VERSION 5.8 ;
BUSBITCHARS "[]" ;
DIVIDERCHAR "/" ;
UNITS
    DATABASE MICRONS 2000 ;
END UNITS

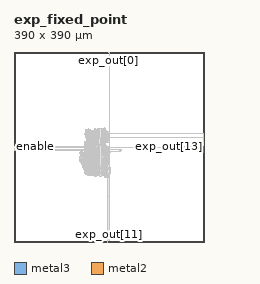
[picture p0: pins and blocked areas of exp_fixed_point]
MACRO exp_fixed_point
  FOREIGN exp_fixed_point 0 0 ;
  CLASS BLOCK ;
  SIZE 390 BY 390 ;
  PIN clk
    DIRECTION INPUT ;
    USE SIGNAL ;
    PORT
      LAYER metal3 ;
        RECT  0 194.915 0.07 194.985 ;
    END
  END clk
  PIN enable
    DIRECTION INPUT ;
    USE SIGNAL ;
    PORT
      LAYER metal3 ;
        RECT  0 195.755 0.07 195.825 ;
    END
  END enable
  PIN exp_out[0]
    DIRECTION OUTPUT ;
    USE SIGNAL ;
    PORT
      LAYER metal2 ;
        RECT  194.24 389.93 194.31 390 ;
    END
  END exp_out[0]
  PIN exp_out[10]
    DIRECTION OUTPUT ;
    USE SIGNAL ;
    PORT
      LAYER metal3 ;
        RECT  0 196.035 0.07 196.105 ;
    END
  END exp_out[10]
  PIN exp_out[11]
    DIRECTION OUTPUT ;
    USE SIGNAL ;
    PORT
      LAYER metal2 ;
        RECT  194.62 0 194.69 0.07 ;
    END
  END exp_out[11]
  PIN exp_out[12]
    DIRECTION OUTPUT ;
    USE SIGNAL ;
    PORT
      LAYER metal2 ;
        RECT  195 0 195.07 0.07 ;
    END
  END exp_out[12]
  PIN exp_out[13]
    DIRECTION OUTPUT ;
    USE SIGNAL ;
    PORT
      LAYER metal3 ;
        RECT  389.93 196.035 390 196.105 ;
    END
  END exp_out[13]
  PIN exp_out[14]
    DIRECTION OUTPUT ;
    USE SIGNAL ;
    PORT
      LAYER metal2 ;
        RECT  196.14 389.93 196.21 390 ;
    END
  END exp_out[14]
  PIN exp_out[15]
    DIRECTION OUTPUT ;
    USE SIGNAL ;
    PORT
      LAYER metal3 ;
        RECT  389.93 195.755 390 195.825 ;
    END
  END exp_out[15]
  PIN exp_out[1]
    DIRECTION OUTPUT ;
    USE SIGNAL ;
    PORT
      LAYER metal2 ;
        RECT  194.24 0 194.31 0.07 ;
    END
  END exp_out[1]
  PIN exp_out[2]
    DIRECTION OUTPUT ;
    USE SIGNAL ;
    PORT
      LAYER metal2 ;
        RECT  196.14 0 196.21 0.07 ;
    END
  END exp_out[2]
  PIN exp_out[3]
    DIRECTION OUTPUT ;
    USE SIGNAL ;
    PORT
      LAYER metal2 ;
        RECT  195.76 389.93 195.83 390 ;
    END
  END exp_out[3]
  PIN exp_out[4]
    DIRECTION OUTPUT ;
    USE SIGNAL ;
    PORT
      LAYER metal3 ;
        RECT  389.93 195.195 390 195.265 ;
    END
  END exp_out[4]
  PIN exp_out[5]
    DIRECTION OUTPUT ;
    USE SIGNAL ;
    PORT
      LAYER metal2 ;
        RECT  195.38 0 195.45 0.07 ;
    END
  END exp_out[5]
  PIN exp_out[6]
    DIRECTION OUTPUT ;
    USE SIGNAL ;
    PORT
      LAYER metal2 ;
        RECT  193.86 0 193.93 0.07 ;
    END
  END exp_out[6]
  PIN exp_out[7]
    DIRECTION OUTPUT ;
    USE SIGNAL ;
    PORT
      LAYER metal3 ;
        RECT  0 195.195 0.07 195.265 ;
    END
  END exp_out[7]
  PIN exp_out[8]
    DIRECTION OUTPUT ;
    USE SIGNAL ;
    PORT
      LAYER metal2 ;
        RECT  193.48 0 193.55 0.07 ;
    END
  END exp_out[8]
  PIN exp_out[9]
    DIRECTION OUTPUT ;
    USE SIGNAL ;
    PORT
      LAYER metal3 ;
        RECT  389.93 194.075 390 194.145 ;
    END
  END exp_out[9]
  PIN rst
    DIRECTION INPUT ;
    USE SIGNAL ;
    PORT
      LAYER metal3 ;
        RECT  0 194.355 0.07 194.425 ;
    END
  END rst
  PIN x_in[0]
    DIRECTION INPUT ;
    USE SIGNAL ;
    PORT
      LAYER metal3 ;
        RECT  389.93 195.475 390 195.545 ;
    END
  END x_in[0]
  PIN x_in[1]
    DIRECTION INPUT ;
    USE SIGNAL ;
    PORT
      LAYER metal2 ;
        RECT  195.76 0 195.83 0.07 ;
    END
  END x_in[1]
  PIN x_in[2]
    DIRECTION INPUT ;
    USE SIGNAL ;
    PORT
      LAYER metal3 ;
        RECT  0 195.475 0.07 195.545 ;
    END
  END x_in[2]
  PIN x_in[3]
    DIRECTION INPUT ;
    USE SIGNAL ;
    PORT
      LAYER metal3 ;
        RECT  0 194.635 0.07 194.705 ;
    END
  END x_in[3]
  PIN x_in[4]
    DIRECTION INPUT ;
    USE SIGNAL ;
    PORT
      LAYER metal2 ;
        RECT  195.38 389.93 195.45 390 ;
    END
  END x_in[4]
  PIN x_in[5]
    DIRECTION INPUT ;
    USE SIGNAL ;
    PORT
      LAYER metal3 ;
        RECT  389.93 194.915 390 194.985 ;
    END
  END x_in[5]
  PIN x_in[6]
    DIRECTION INPUT ;
    USE SIGNAL ;
    PORT
      LAYER metal2 ;
        RECT  195 389.93 195.07 390 ;
    END
  END x_in[6]
  PIN x_in[7]
    DIRECTION INPUT ;
    USE SIGNAL ;
    PORT
      LAYER metal2 ;
        RECT  194.62 389.93 194.69 390 ;
    END
  END x_in[7]
  OBS
    LAYER metal1 ;
     RECT  133.95 173.515 134.9 175.085 ;
     RECT  134.9 172.115 135.09 175.085 ;
     RECT  135.09 172.115 135.28 176.485 ;
     RECT  135.28 167.915 135.66 176.485 ;
     RECT  135.09 181.915 135.66 183.485 ;
     RECT  135.66 167.915 136.61 183.485 ;
     RECT  136.61 163.715 136.8 183.485 ;
     RECT  136.8 163.715 137.94 184.885 ;
     RECT  137.94 162.315 138.7 184.885 ;
     RECT  138.7 160.915 138.89 184.885 ;
     RECT  138.89 159.515 140.22 184.885 ;
     RECT  140.22 159.515 141.55 183.485 ;
     RECT  141.55 156.715 142.31 183.485 ;
     RECT  142.31 153.915 142.5 183.485 ;
     RECT  142.5 148.315 144.59 183.485 ;
     RECT  143.45 193.115 144.78 194.685 ;
     RECT  144.21 198.715 144.78 200.285 ;
     RECT  144.59 144.115 145.16 183.485 ;
     RECT  144.78 190.315 145.16 200.285 ;
     RECT  145.16 142.715 145.35 183.485 ;
     RECT  145.16 190.315 145.35 201.685 ;
     RECT  145.35 139.915 145.54 183.485 ;
     RECT  145.35 190.315 145.54 203.085 ;
     RECT  145.73 221.115 146.3 222.685 ;
     RECT  145.54 139.915 146.68 205.885 ;
     RECT  146.49 228.115 146.68 229.685 ;
     RECT  146.3 219.715 147.06 222.685 ;
     RECT  146.68 226.715 147.06 229.685 ;
     RECT  147.06 219.715 147.25 229.685 ;
     RECT  147.25 215.515 147.63 229.685 ;
     RECT  146.68 138.515 149.15 205.885 ;
     RECT  149.15 138.515 149.91 210.085 ;
     RECT  147.63 215.515 149.91 231.085 ;
     RECT  149.91 138.515 150.29 231.085 ;
     RECT  150.29 137.115 152.76 231.085 ;
     RECT  152.76 137.115 153.14 232.485 ;
     RECT  153.14 137.115 156.75 231.085 ;
     RECT  156.75 137.115 158.46 229.685 ;
     RECT  158.46 137.115 159.41 226.885 ;
     RECT  159.41 135.715 161.88 226.885 ;
     RECT  161.88 135.715 164.73 229.685 ;
     RECT  164.73 135.715 166.06 231.085 ;
     RECT  166.06 134.315 166.63 232.485 ;
     RECT  166.63 134.315 168.53 231.085 ;
     RECT  168.53 135.715 170.43 231.085 ;
     RECT  170.43 137.115 174.04 232.485 ;
     RECT  174.04 135.715 179.74 233.885 ;
     RECT  179.74 134.315 180.31 233.885 ;
     RECT  180.31 135.715 180.88 233.885 ;
     RECT  180.88 135.715 183.92 232.485 ;
     RECT  183.92 135.715 185.25 233.885 ;
     RECT  185.25 135.715 185.63 235.285 ;
     RECT  185.63 134.315 185.82 235.285 ;
     RECT  185.82 132.915 186.01 235.285 ;
     RECT  186.01 132.915 186.96 233.885 ;
     RECT  186.96 202.915 187.15 233.885 ;
     RECT  187.15 204.315 187.53 233.885 ;
     RECT  187.53 204.315 187.72 232.485 ;
     RECT  187.72 209.915 188.1 232.485 ;
     RECT  186.96 132.915 188.67 198.885 ;
     RECT  188.1 209.915 188.86 229.685 ;
     RECT  188.86 209.915 190 228.285 ;
     RECT  188.67 134.315 190.19 198.885 ;
     RECT  187.72 204.315 190.38 205.885 ;
     RECT  190.19 135.715 190.57 198.885 ;
     RECT  190.57 135.715 191.52 196.085 ;
     RECT  190 209.915 191.71 225.485 ;
     RECT  191.71 211.315 192.47 225.485 ;
     RECT  191.52 135.715 193.04 194.685 ;
     RECT  193.04 135.715 193.42 186.285 ;
     RECT  192.47 211.315 193.42 224.085 ;
     RECT  193.42 134.315 193.8 186.285 ;
     RECT  193.42 212.715 193.8 224.085 ;
     RECT  193.8 218.315 193.99 224.085 ;
     RECT  193.8 135.715 194.56 186.285 ;
     RECT  193.8 212.715 194.75 214.285 ;
     RECT  194.56 135.715 194.94 137.285 ;
     RECT  194.56 142.715 194.94 186.285 ;
     RECT  193.99 218.315 194.94 219.885 ;
     RECT  193.04 191.715 195.13 194.685 ;
     RECT  194.56 47.515 195.32 49.085 ;
     RECT  194.94 159.515 195.32 186.285 ;
     RECT  195.13 191.715 195.32 193.285 ;
     RECT  194.94 142.715 195.89 155.485 ;
     RECT  195.32 159.515 195.89 177.885 ;
     RECT  195.89 159.515 196.08 168.085 ;
     RECT  196.08 162.315 196.27 165.285 ;
     RECT  195.89 174.915 196.27 177.885 ;
     RECT  196.08 341.515 196.46 343.085 ;
     RECT  196.27 162.315 196.65 163.885 ;
     RECT  195.32 183.315 196.65 186.285 ;
     RECT  195.89 142.715 196.84 151.285 ;
     RECT  196.27 176.315 197.03 177.885 ;
     RECT  196.84 142.715 197.98 142.885 ;
     RECT  196.65 184.715 198.36 186.285 ;
     RECT  197.98 141.315 198.55 142.885 ;
     RECT  196.84 148.315 198.74 151.285 ;
     RECT  216.98 187.515 220.21 189.085 ;
     RECT  342.57 195.915 343.33 197.485 ;
    LAYER metal2 ;
     RECT  192.34 0 196.97 94.085 ;
     RECT  187.4 133.28 188.42 133.315 ;
     RECT  192.53 94.085 196.97 133.315 ;
     RECT  186.64 133.315 196.97 133.56 ;
     RECT  167.07 134.54 167.14 134.575 ;
     RECT  167.07 134.575 168.09 134.82 ;
     RECT  166.69 134.82 168.09 134.855 ;
     RECT  165.93 134.855 168.09 135.1 ;
     RECT  185.88 133.56 196.97 135.1 ;
     RECT  165.74 135.1 168.28 135.52 ;
     RECT  165.74 135.52 169.8 135.94 ;
     RECT  160.61 135.94 169.8 136.08 ;
     RECT  175.24 135.1 175.31 136.08 ;
     RECT  179.8 135.1 180.25 136.08 ;
     RECT  185.69 135.1 196.97 136.08 ;
     RECT  159.85 136.08 170.18 136.115 ;
     RECT  159.85 136.115 170.56 136.22 ;
     RECT  175.24 136.08 196.97 136.22 ;
     RECT  159.85 136.22 196.97 136.36 ;
     RECT  159.47 136.36 196.97 137.48 ;
     RECT  151.68 137.62 151.75 137.655 ;
     RECT  151.3 137.655 151.75 137.9 ;
     RECT  155.67 137.48 196.97 137.9 ;
     RECT  150.35 137.9 196.97 137.935 ;
     RECT  150.16 137.935 196.97 138.32 ;
     RECT  149.4 138.32 196.97 138.88 ;
     RECT  149.02 138.88 196.97 139.02 ;
     RECT  146.93 139.02 196.97 139.16 ;
     RECT  146.74 139.16 196.97 139.195 ;
     RECT  146.55 139.195 196.97 140.56 ;
     RECT  145.6 140.56 196.97 140.7 ;
     RECT  145.41 140.7 196.97 141.96 ;
     RECT  144.46 141.96 198.49 148.68 ;
     RECT  143.51 148.68 198.49 148.82 ;
     RECT  143.32 148.82 198.49 148.855 ;
     RECT  142.94 148.855 198.49 149.1 ;
     RECT  142.56 149.1 198.68 150.22 ;
     RECT  142.37 150.22 198.68 150.78 ;
     RECT  142.37 150.78 198.11 151.06 ;
     RECT  142.37 151.06 197.54 151.2 ;
     RECT  142.37 151.2 197.35 151.34 ;
     RECT  142.37 151.34 197.16 151.9 ;
     RECT  142.37 151.9 196.97 153.16 ;
     RECT  141.61 153.16 196.97 157.5 ;
     RECT  140.85 157.5 196.97 157.92 ;
     RECT  140.28 157.92 196.97 160.3 ;
     RECT  138.95 160.3 196.97 161.56 ;
     RECT  138.76 161.56 196.97 162.68 ;
     RECT  137.81 162.68 196.97 164.08 ;
     RECT  135.72 164.08 196.97 166.04 ;
     RECT  135.15 166.04 196.97 169.96 ;
     RECT  134.2 169.96 196.97 171.5 ;
     RECT  134.01 171.5 196.97 175.14 ;
     RECT  134.2 175.14 196.97 175.98 ;
     RECT  135.72 175.98 196.97 176.82 ;
     RECT  135.72 176.82 196.59 181.44 ;
     RECT  135.15 181.44 196.59 182.84 ;
     RECT  135.34 182.84 196.59 183.12 ;
     RECT  136.29 183.12 196.59 183.225 ;
     RECT  136.86 183.225 196.59 183.68 ;
     RECT  136.86 183.68 139.78 184.1 ;
     RECT  139.71 184.1 139.78 184.24 ;
     RECT  144.27 183.68 196.59 185.08 ;
     RECT  145.6 185.08 196.59 185.22 ;
     RECT  218.56 185.22 218.63 185.36 ;
     RECT  145.6 185.22 197.16 185.64 ;
     RECT  217.8 185.36 218.63 188.44 ;
     RECT  0.63 188.72 0.7 188.86 ;
     RECT  220.08 188.58 220.15 189 ;
     RECT  0.44 188.86 0.7 189.56 ;
     RECT  145.6 185.64 196.59 190.54 ;
     RECT  145.41 190.54 196.59 191.1 ;
     RECT  144.84 191.1 196.59 193.76 ;
     RECT  143.7 193.76 196.59 193.9 ;
     RECT  389.75 193.76 389.82 194.88 ;
     RECT  0.06 189.56 0.7 195.02 ;
     RECT  143.51 193.9 196.59 195.02 ;
     RECT  0.44 195.02 0.7 195.3 ;
     RECT  389.56 194.88 389.82 195.3 ;
     RECT  389.56 195.3 389.63 195.44 ;
     RECT  143.51 195.02 190.89 195.58 ;
     RECT  143.51 195.58 190.51 195.86 ;
     RECT  342.63 195.72 342.7 196 ;
     RECT  0.63 195.3 0.7 196.14 ;
     RECT  342.63 196 343.08 196.7 ;
     RECT  144.27 195.86 190.51 197.82 ;
     RECT  144.27 197.82 189.56 198.1 ;
     RECT  144.27 198.1 186.14 199.64 ;
     RECT  144.65 199.64 186.14 199.78 ;
     RECT  145.22 199.78 186.14 200.9 ;
     RECT  145.6 200.9 186.14 201.425 ;
     RECT  145.79 201.425 186.14 202.02 ;
     RECT  145.79 202.02 186.9 202.3 ;
     RECT  145.79 202.3 187.47 204.82 ;
     RECT  195.19 195.02 196.59 204.82 ;
     RECT  145.79 204.82 187.66 204.96 ;
     RECT  191.96 204.82 196.59 204.96 ;
     RECT  145.79 204.96 196.59 205.24 ;
     RECT  145.79 205.24 187.85 205.38 ;
     RECT  145.98 205.38 187.85 205.52 ;
     RECT  147.88 205.52 187.85 209.16 ;
     RECT  191.96 205.24 196.59 209.16 ;
     RECT  389.37 195.44 389.63 214.76 ;
     RECT  147.88 209.16 196.59 216.02 ;
     RECT  147.31 216.02 196.59 220.36 ;
     RECT  146.36 220.36 196.59 221.62 ;
     RECT  145.79 221.62 196.59 222.04 ;
     RECT  389.56 214.76 389.63 222.04 ;
     RECT  146.17 222.04 196.59 222.46 ;
     RECT  146.36 222.46 196.59 223.265 ;
     RECT  146.55 223.265 196.59 227.08 ;
     RECT  146.55 227.08 189.94 228.445 ;
     RECT  146.55 228.445 188.8 228.9 ;
     RECT  146.74 228.9 158.4 229.18 ;
     RECT  162.32 228.9 188.42 229.18 ;
     RECT  162.32 229.18 188.04 229.32 ;
     RECT  146.74 229.18 156.5 229.46 ;
     RECT  164.22 229.32 188.04 230.125 ;
     RECT  146.74 229.46 156.31 230.44 ;
     RECT  164.79 230.125 188.04 230.44 ;
     RECT  151.68 230.44 155.93 230.58 ;
     RECT  151.68 230.58 153.84 230.72 ;
     RECT  152.82 230.72 153.84 231.245 ;
     RECT  152.82 231.245 153.08 231.28 ;
     RECT  165.36 230.44 188.04 231.665 ;
     RECT  152.82 231.28 152.89 231.7 ;
     RECT  165.36 231.665 166.57 231.7 ;
     RECT  170.49 231.665 188.04 231.7 ;
     RECT  165.36 231.7 166.38 231.945 ;
     RECT  166.31 231.945 166.38 231.98 ;
     RECT  173.34 231.7 188.04 231.98 ;
     RECT  173.34 231.98 187.47 232.26 ;
     RECT  174.1 232.26 187.28 233.24 ;
     RECT  176.38 233.24 180.25 233.38 ;
     RECT  184.55 233.24 187.28 233.38 ;
     RECT  176.38 233.38 179.3 233.52 ;
     RECT  185.12 233.38 187.28 233.735 ;
     RECT  185.31 233.735 186.71 234.465 ;
     RECT  185.31 234.465 185.76 234.5 ;
     RECT  195 227.08 196.59 389.48 ;
     RECT  194.24 389.48 196.59 389.62 ;
     RECT  194.24 389.62 196.21 389.965 ;
    LAYER metal3 ;
     RECT  0.025 194.915 0.035 194.985 ;
     RECT  0.025 189.595 0.405 189.665 ;
     RECT  0.405 188.895 0.595 189.665 ;
     RECT  0.035 194.355 0.735 196.105 ;
     RECT  0.595 188.755 133.915 189.665 ;
     RECT  0.735 194.355 133.915 195.825 ;
     RECT  133.975 171.535 134.165 171.605 ;
     RECT  133.975 175.035 134.165 175.105 ;
     RECT  134.165 169.995 134.355 171.605 ;
     RECT  134.165 175.035 134.355 175.945 ;
     RECT  134.355 169.995 135.495 175.945 ;
     RECT  135.115 181.475 135.495 181.545 ;
     RECT  135.115 166.075 135.685 166.145 ;
     RECT  135.495 169.155 135.685 175.945 ;
     RECT  135.495 181.475 135.685 182.665 ;
     RECT  135.685 164.115 136.255 166.145 ;
     RECT  135.685 169.155 136.255 182.665 ;
     RECT  136.255 164.115 136.445 182.665 ;
     RECT  136.445 164.115 136.67 182.945 ;
     RECT  136.67 164.115 137.205 183.085 ;
     RECT  137.205 164.115 137.775 183.645 ;
     RECT  137.775 162.715 138.915 183.645 ;
     RECT  138.915 160.335 139.675 183.645 ;
     RECT  139.675 160.335 140.245 184.205 ;
     RECT  140.245 157.955 140.815 184.205 ;
     RECT  141.575 153.195 141.765 153.265 ;
     RECT  140.815 157.535 141.765 184.205 ;
     RECT  142.335 150.255 142.715 150.325 ;
     RECT  141.765 153.195 142.715 184.205 ;
     RECT  142.715 149.275 143.095 184.205 ;
     RECT  143.095 149.135 143.285 184.205 ;
     RECT  143.285 148.855 143.475 184.205 ;
     RECT  133.915 193.935 143.665 195.825 ;
     RECT  143.475 148.715 144.235 184.205 ;
     RECT  144.425 141.995 144.615 142.065 ;
     RECT  144.235 148.715 144.615 185.045 ;
     RECT  144.235 199.535 144.615 199.605 ;
     RECT  133.915 188.615 144.805 189.665 ;
     RECT  143.665 193.795 144.805 195.825 ;
     RECT  144.615 199.115 144.805 199.745 ;
     RECT  144.615 141.995 145.375 185.045 ;
     RECT  145.375 140.735 145.565 185.045 ;
     RECT  144.805 188.615 145.565 199.745 ;
     RECT  145.565 188.055 145.945 199.745 ;
     RECT  145.755 204.715 145.945 204.785 ;
     RECT  145.755 221.655 146.135 221.725 ;
     RECT  146.135 221.655 146.325 222.425 ;
     RECT  145.565 140.595 146.705 185.045 ;
     RECT  146.705 139.475 146.895 185.045 ;
     RECT  145.945 188.055 146.895 205.485 ;
     RECT  146.515 226.275 146.895 226.345 ;
     RECT  146.705 230.335 146.895 230.405 ;
     RECT  146.325 220.395 147.085 222.425 ;
     RECT  146.895 226.275 147.085 226.625 ;
     RECT  146.895 229.775 147.085 230.405 ;
     RECT  147.085 220.395 147.275 230.405 ;
     RECT  147.275 216.055 147.465 216.125 ;
     RECT  147.275 219.975 147.465 230.405 ;
     RECT  146.895 139.055 148.985 205.485 ;
     RECT  148.985 138.915 149.175 205.485 ;
     RECT  149.175 138.915 149.365 205.765 ;
     RECT  148.415 209.755 149.365 209.825 ;
     RECT  147.465 216.055 149.365 230.405 ;
     RECT  149.365 138.355 149.935 209.825 ;
     RECT  149.935 138.355 150.125 212.065 ;
     RECT  149.365 215.915 150.125 230.405 ;
     RECT  150.125 138.355 151.265 230.405 ;
     RECT  151.265 138.215 151.645 230.405 ;
     RECT  151.645 138.215 151.835 230.685 ;
     RECT  151.835 137.935 153.495 230.685 ;
     RECT  153.495 137.935 155.635 230.405 ;
     RECT  155.635 137.515 156.345 230.405 ;
     RECT  156.345 137.515 158.05 229.005 ;
     RECT  158.05 137.515 158.245 228.865 ;
     RECT  158.245 137.515 159.435 228.725 ;
     RECT  159.435 136.395 162.095 228.725 ;
     RECT  162.095 136.395 162.285 228.865 ;
     RECT  162.285 136.395 162.475 229.285 ;
     RECT  162.475 136.255 163.235 229.285 ;
     RECT  163.235 136.115 164.185 229.285 ;
     RECT  164.185 135.975 164.755 229.285 ;
     RECT  164.755 135.975 165.265 230.405 ;
     RECT  165.265 135.555 165.705 230.405 ;
     RECT  165.705 135.135 166.415 230.685 ;
     RECT  166.415 135.555 169.125 230.685 ;
     RECT  169.125 135.555 169.835 230.825 ;
     RECT  169.835 137.655 170.835 230.825 ;
     RECT  170.835 137.655 172.925 230.965 ;
     RECT  172.925 136.815 173.305 230.965 ;
     RECT  173.305 136.815 174.065 232.225 ;
     RECT  174.065 136.255 175.205 232.225 ;
     RECT  175.205 135.135 175.585 232.225 ;
     RECT  175.585 135.135 176.345 233.205 ;
     RECT  176.345 135.135 180.285 233.485 ;
     RECT  180.285 136.115 180.855 233.485 ;
     RECT  180.855 136.115 182.565 228.025 ;
     RECT  182.565 136.395 182.945 228.025 ;
     RECT  182.945 136.955 184.845 228.025 ;
     RECT  184.845 202.055 184.895 228.025 ;
     RECT  180.855 230.895 184.895 233.485 ;
     RECT  184.845 136.955 185.225 198.345 ;
     RECT  185.225 136.955 185.845 198.065 ;
     RECT  185.845 135.135 186.035 198.065 ;
     RECT  184.895 202.055 186.935 233.485 ;
     RECT  186.035 134.855 186.985 198.065 ;
     RECT  186.935 202.335 187.125 233.205 ;
     RECT  187.125 202.335 187.505 232.225 ;
     RECT  187.505 209.195 187.885 231.525 ;
     RECT  187.885 209.195 188.455 229.145 ;
     RECT  188.455 209.195 188.645 228.725 ;
     RECT  186.985 133.595 189.025 198.065 ;
     RECT  188.645 209.195 189.405 227.325 ;
     RECT  189.025 135.555 189.595 198.065 ;
     RECT  189.405 209.195 189.595 227.045 ;
     RECT  189.595 135.555 189.785 195.545 ;
     RECT  189.785 135.835 190.165 195.545 ;
     RECT  190.165 135.835 190.545 195.265 ;
     RECT  190.545 135.975 190.925 195.265 ;
     RECT  190.925 135.975 191.685 194.145 ;
     RECT  187.505 204.855 192.065 205.205 ;
     RECT  189.595 210.175 192.635 227.045 ;
     RECT  192.635 226.975 192.825 227.045 ;
     RECT  191.685 176.715 193.015 194.145 ;
     RECT  192.065 205.135 193.015 205.205 ;
     RECT  193.015 176.715 193.395 181.265 ;
     RECT  192.635 210.175 193.395 223.545 ;
     RECT  193.015 184.135 193.585 194.145 ;
     RECT  193.585 184.135 193.775 190.925 ;
     RECT  193.395 210.175 193.775 223.405 ;
     RECT  193.775 184.135 193.835 185.885 ;
     RECT  191.685 135.975 193.965 172.865 ;
     RECT  193.395 176.855 193.965 178.045 ;
     RECT  193.965 135.975 194.155 172.445 ;
     RECT  193.825 1.015 194.205 1.085 ;
     RECT  194.155 136.255 194.345 171.885 ;
     RECT  193.775 218.715 194.345 223.405 ;
     RECT  194.345 136.395 194.535 171.885 ;
     RECT  193.965 177.415 194.535 178.045 ;
     RECT  193.775 210.175 194.535 215.005 ;
     RECT  194.205 389.515 194.585 389.585 ;
     RECT  194.535 177.695 194.725 178.045 ;
     RECT  194.345 219.135 194.725 223.405 ;
     RECT  194.535 136.535 194.915 155.645 ;
     RECT  194.535 210.175 194.915 214.725 ;
     RECT  194.725 220.395 194.915 223.405 ;
     RECT  194.915 138.915 195.105 155.645 ;
     RECT  194.915 221.935 195.105 223.405 ;
     RECT  194.585 389.515 195.155 389.725 ;
     RECT  194.205 0.175 195.295 1.085 ;
     RECT  195.105 139.615 195.295 155.645 ;
     RECT  195.295 139.615 195.485 153.825 ;
     RECT  194.535 170.975 195.485 171.885 ;
     RECT  193.395 181.195 195.485 181.265 ;
     RECT  194.535 159.495 195.605 167.825 ;
     RECT  195.605 160.195 195.675 167.825 ;
     RECT  194.915 210.175 195.675 214.585 ;
     RECT  195.485 170.975 195.865 171.325 ;
     RECT  195.155 389.515 195.865 389.865 ;
     RECT  195.295 1.015 196.055 1.085 ;
     RECT  195.675 160.335 196.055 167.825 ;
     RECT  194.725 177.695 196.055 177.765 ;
     RECT  196.055 162.295 196.21 167.825 ;
     RECT  196.21 162.295 196.245 165.585 ;
     RECT  195.675 210.175 196.245 210.245 ;
     RECT  195.485 139.615 196.435 152.005 ;
     RECT  196.245 162.295 196.445 164.745 ;
     RECT  196.445 162.575 196.625 164.745 ;
     RECT  193.835 184.135 196.625 185.465 ;
     RECT  193.775 188.895 196.625 190.925 ;
     RECT  195.865 389.515 196.625 389.585 ;
     RECT  196.435 145.635 196.815 152.005 ;
     RECT  196.625 162.575 196.815 162.645 ;
     RECT  196.435 139.615 197.005 139.685 ;
     RECT  196.815 145.635 197.195 151.865 ;
     RECT  197.195 145.635 197.385 151.305 ;
     RECT  197.385 145.635 197.575 151.165 ;
     RECT  197.575 145.635 198.145 151.025 ;
     RECT  198.145 145.635 198.335 145.705 ;
     RECT  198.145 148.715 198.525 150.185 ;
     RECT  198.525 149.135 198.715 149.205 ;
     RECT  195.675 214.515 213.715 214.585 ;
     RECT  213.715 214.515 213.785 214.725 ;
     RECT  196.625 185.255 217.905 185.465 ;
     RECT  217.905 185.255 218.665 185.325 ;
     RECT  196.625 188.895 220.185 188.965 ;
     RECT  193.585 193.795 342.595 194.145 ;
     RECT  342.595 193.795 342.975 195.825 ;
     RECT  213.785 214.655 389.475 214.725 ;
     RECT  195.105 221.935 389.665 222.005 ;
     RECT  342.975 193.795 389.855 196.105 ;
     RECT  389.855 194.075 389.965 196.105 ;
    LAYER metal4 ;
     RECT  175.865 136.36 176.005 139.72 ;
     RECT  196.865 139.58 197.005 139.72 ;
     RECT  175.865 139.72 177.125 141.68 ;
     RECT  175.865 141.68 177.405 142.52 ;
     RECT  174.745 142.52 177.405 143.78 ;
     RECT  174.745 143.78 180.205 147.84 ;
     RECT  190.985 139.72 197.005 147.84 ;
     RECT  168.865 146.44 169.005 148.82 ;
     RECT  143.665 149.24 143.805 150.78 ;
     RECT  174.745 147.84 197.005 150.78 ;
     RECT  174.745 150.78 196.445 151.9 ;
     RECT  160.745 147.56 160.885 152.04 ;
     RECT  174.745 151.9 195.605 152.74 ;
     RECT  143.665 150.78 144.085 153.02 ;
     RECT  142.825 153.02 144.085 153.16 ;
     RECT  174.745 152.74 180.205 153.72 ;
     RECT  142.825 153.16 144.365 155.68 ;
     RECT  174.745 153.72 179.925 156.8 ;
     RECT  179.785 156.8 179.925 157.92 ;
     RECT  142.825 155.68 143.805 158.2 ;
     RECT  190.985 152.74 195.605 159.46 ;
     RECT  142.825 158.2 142.965 159.6 ;
     RECT  151.785 149.24 151.925 159.74 ;
     RECT  162.425 159.6 162.565 159.74 ;
     RECT  185.105 160.02 186.085 160.58 ;
     RECT  151.505 159.74 153.325 161.7 ;
     RECT  160.745 159.74 162.565 161.98 ;
     RECT  194.625 159.46 195.605 162.26 ;
     RECT  162.425 161.98 162.565 163.66 ;
     RECT  173.905 159.6 174.045 163.66 ;
     RECT  148.705 161.7 153.325 164.08 ;
     RECT  185.105 160.58 185.245 164.36 ;
     RECT  194.625 162.26 196.445 164.78 ;
     RECT  194.625 164.78 196.165 165.62 ;
     RECT  141.425 159.6 142.965 166.04 ;
     RECT  150.945 164.08 153.325 169.96 ;
     RECT  194.625 165.62 195.045 169.96 ;
     RECT  152.625 169.96 153.325 170.1 ;
     RECT  141.425 166.04 141.565 171.08 ;
     RECT  162.705 168.84 162.845 171.5 ;
     RECT  179.505 169.26 179.645 171.5 ;
     RECT  185.385 170.94 185.525 171.5 ;
     RECT  193.785 169.96 195.045 171.64 ;
     RECT  179.505 171.5 185.525 171.78 ;
     RECT  162.425 171.5 162.845 172.48 ;
     RECT  193.785 171.64 193.925 172.9 ;
     RECT  152.625 170.1 153.045 174.3 ;
     RECT  152.905 174.3 153.045 174.72 ;
     RECT  136.945 171.08 141.565 175.56 ;
     RECT  179.505 171.78 184.125 177.66 ;
     RECT  183.985 177.66 184.125 177.94 ;
     RECT  141.425 175.56 141.565 178.08 ;
     RECT  162.425 172.48 163.125 178.92 ;
     RECT  165.505 179.06 165.645 181.72 ;
     RECT  190.985 182.28 191.125 184.8 ;
     RECT  182.865 184.24 183.005 184.94 ;
     RECT  182.305 184.94 183.005 185.08 ;
     RECT  172.505 185.22 172.645 185.5 ;
     RECT  179.505 185.08 183.005 186.48 ;
     RECT  182.865 186.48 183.005 189.42 ;
     RECT  170.545 185.5 172.645 192.22 ;
     RECT  170.545 192.22 170.685 194.04 ;
     RECT  152.065 195.3 152.205 196.56 ;
     RECT  166.625 194.04 170.685 198.24 ;
     RECT  166.625 198.24 166.765 198.38 ;
     RECT  151.505 196.56 152.205 198.66 ;
     RECT  165.505 199.08 165.645 199.64 ;
     RECT  178.385 197.54 178.525 201.04 ;
     RECT  151.505 198.66 152.765 201.74 ;
     RECT  150.945 201.74 152.765 204.26 ;
     RECT  163.265 199.64 165.645 205.24 ;
     RECT  150.945 204.26 153.045 206.36 ;
     RECT  150.945 206.36 152.485 206.78 ;
     RECT  163.265 205.24 163.685 207.76 ;
     RECT  173.345 201.04 178.525 211.82 ;
     RECT  173.345 211.82 173.485 213.64 ;
     RECT  150.945 206.78 151.085 216.3 ;
     RECT  163.545 207.76 163.685 219.52 ;
     RECT  163.545 219.52 166.205 219.94 ;
     RECT  162.425 219.94 166.205 220.92 ;
     RECT  172.785 219.52 172.925 225.26 ;
     RECT  179.225 224 179.365 225.96 ;
     RECT  162.425 220.92 162.565 228.62 ;
     RECT  149.265 219.94 149.405 229.04 ;
  END
END exp_fixed_point
END LIBRARY
